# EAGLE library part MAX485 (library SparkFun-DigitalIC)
RS-485 transceiver

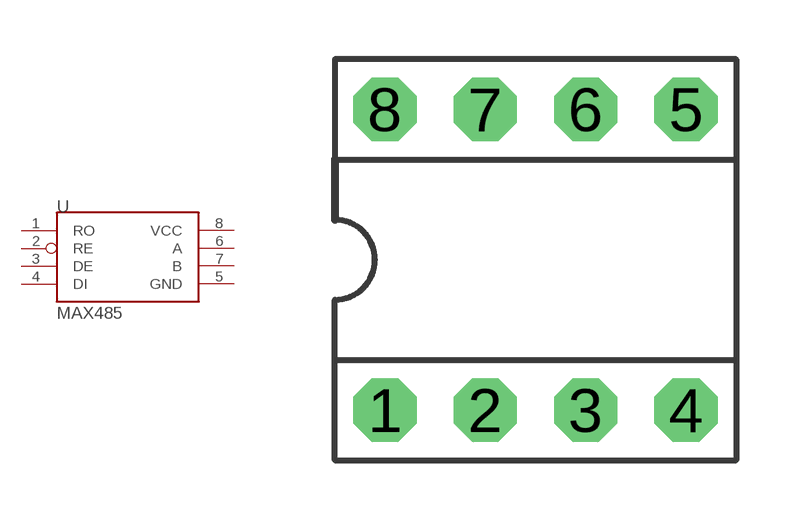
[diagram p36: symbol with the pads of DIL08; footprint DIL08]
Designator prefix -

## MAX485DIL  [DIL08]
1  RO
2  RE
3  DE
4  DI
5  GND
6  A
7  B
8  VCC

## Footprint DIL08 (pad centres in mm)
Dual In Line
drill 0.813 pad 1.6 octagon: 1 -3.81,-3.81; 2 -1.27,-3.81; 3 1.27,-3.81; 4 3.81,-3.81; 5 3.81,3.81; 6 1.27,3.81; 7 -1.27,3.81; 8 -3.81,3.81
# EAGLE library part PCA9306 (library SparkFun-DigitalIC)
Bidirectional I2C level shifter. NOT compatible with all available part number pinout schemes- DOUBLE CHECK!!!

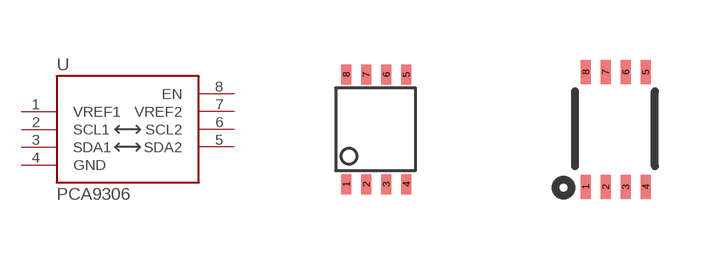
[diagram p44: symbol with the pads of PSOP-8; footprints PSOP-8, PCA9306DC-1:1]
Designator prefix U

## PCA9306 (PROD_ID: IC-10023; VALUE: PCA9306)  [PSOP-8]
1  VREF1
2  SCL1
3  SDA1
4  GND
5  SDA2
6  SCL2
7  VREF2
8  EN

## PCA9306PCA9306DC-1:1 (PROD_ID: IC-10023; VALUE: PCA9306)  [PCA9306DC-1:1]
Pads as for PSOP-8

## Footprint PSOP-8 (pad centres in mm)
smd 0.25 x 0.5: 1 -0.73,-1.37; 2 -0.23,-1.37; 3 0.27,-1.37; 4 0.77,-1.37; 5 0.77,1.38; 6 0.27,1.38; 7 -0.23,1.38; 8 -0.73,1.38

## Footprint PCA9306DC-1:1 (pad centres in mm)
smd 0.25 x 0.602: 1 -0.73,-1.446; 2 -0.23,-1.446; 3 0.27,-1.446; 4 0.77,-1.446; 5 0.77,1.431; 6 0.27,1.431; 7 -0.23,1.431; 8 -0.73,1.431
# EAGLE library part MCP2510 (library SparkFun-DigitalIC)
CAN controller with SPI interface to any MCU. Original design by Microchip.

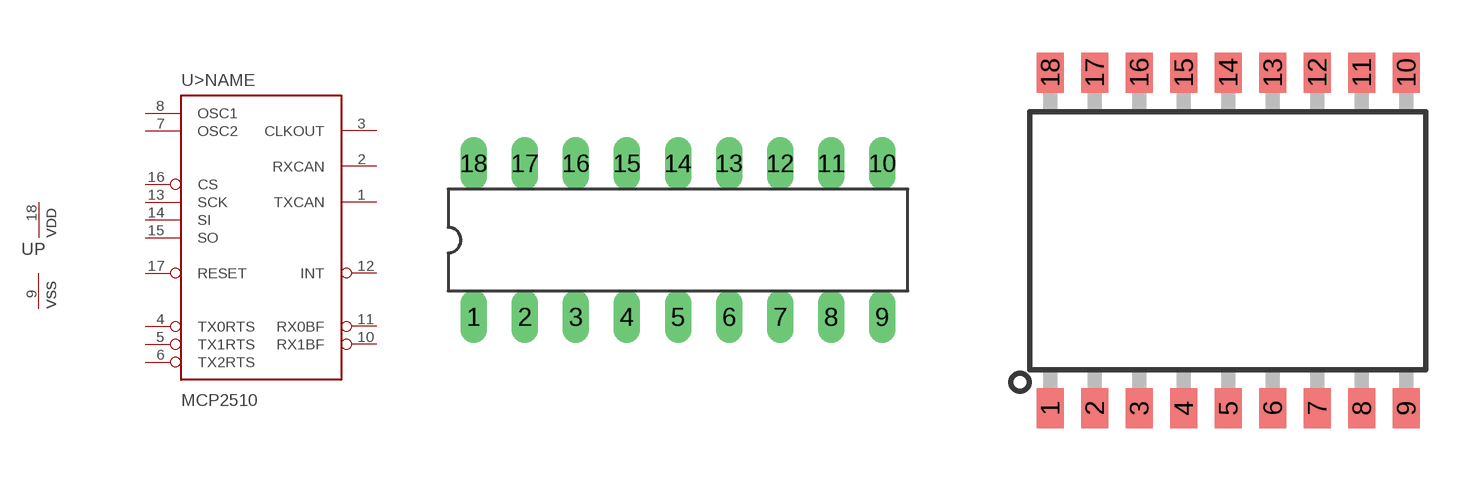
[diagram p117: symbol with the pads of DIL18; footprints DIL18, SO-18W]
Designator prefix U; gates >NAME=MCP2510 P=PWRN-1

## MCP2510P  [DIL18]
1  >NAME:TXCAN  out
2  >NAME:RXCAN  in
3  >NAME:CLKOUT  out
4  >NAME:TX0RTS  in
5  >NAME:TX1RTS  in
6  >NAME:TX2RTS  in
7  >NAME:OSC2  out
8  >NAME:OSC1  in
9  P:VSS  pwr
10  >NAME:RX1BF  out
11  >NAME:RX0BF  out
12  >NAME:INT  out
13  >NAME:SCK  in
14  >NAME:SI  in
15  >NAME:SO  out
16  >NAME:CS  in
17  >NAME:RESET  in
18  P:VDD  pwr

## MCP2510SO (PROD_ID: IC-09906)  [SO-18W]
Pads as for DIL18

## Footprint DIL18 (pad centres in mm)
Dual In Line package type P
drill 0.813 long: 1 -10.16,-3.81; 2 -7.62,-3.81; 3 -5.08,-3.81; 4 -2.54,-3.81; 5 0,-3.81; 6 2.54,-3.81; 7 5.08,-3.81; 8 7.62,-3.81; 9 10.16,-3.81; 10 10.16,3.81; 11 7.62,3.81; 12 5.08,3.81; 13 2.54,3.81; 14 0,3.81; 15 -2.54,3.81; 16 -5.08,3.81; 17 -7.62,3.81; 18 -10.16,3.81

## Footprint SO-18W (pad centres in mm)
Small Outline Wide Plastic Gull Wing 300-mil body, package type SO
smd 0.762 x 1.143: 1 -5.08,-4.788; 2 -3.81,-4.788; 3 -2.54,-4.788; 4 -1.27,-4.788; 5 0,-4.788; 6 1.27,-4.788; 7 2.54,-4.788; 8 3.81,-4.788; 9 5.08,-4.788; 10 5.08,4.788; 11 3.81,4.788; 12 2.54,4.788; 13 1.27,4.788; 14 0,4.788; 15 -1.27,4.788; 16 -2.54,4.788; 17 -3.81,4.788; 18 -5.08,4.788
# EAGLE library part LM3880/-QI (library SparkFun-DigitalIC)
Simple Power Sequencer Precision enable pin & 3 open-drain output flags Input Voltage Range of 2.7 V to 5.5 V Power-Up and Power-Down Control LM3880MF-1XY (Timing Designator) AF16ms AE2ms AA10ms AB30ms AC60ms AD120ms The timing sequence of the LM3880 is controlled entirely by the enable (EN) pin. Upon power up, all the flags are held low until this precision enable is pulled high

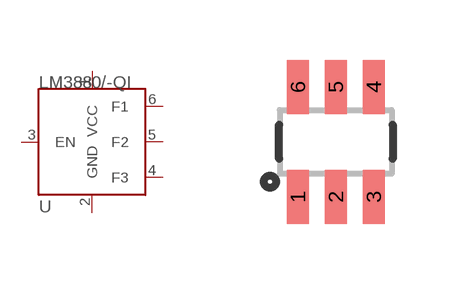
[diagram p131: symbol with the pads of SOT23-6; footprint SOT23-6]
Designator prefix U

## LM3880/-QI (PROD_ID: PROTOTYPE; VALUE: LM3880)  [SOT23-6]
1  VCC
2  GND
3  EN
4  F3
5  F2
6  F1

## Footprint SOT23-6 (pad centres in mm)
smd 0.55 x 1.35: 1 -0.95,-1.375; 2 0,-1.375; 3 0.95,-1.375; 4 0.95,1.375; 5 0,1.375; 6 -0.95,1.375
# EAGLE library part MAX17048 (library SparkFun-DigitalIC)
Micropower 1-Cell Li+ ModelGauge

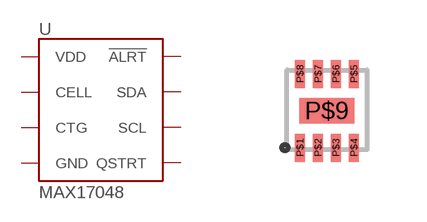
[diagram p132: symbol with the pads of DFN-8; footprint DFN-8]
Designator prefix -

## MAX17048DFN8  [DFN-8]
P$1  CTG  in
P$2  CELL  in
P$3  VDD
P$4  GND
P$5  !ALRT
P$6  QSTRT
P$7  SCL  out
P$8  SDA  in
P$9  GND

## Footprint DFN-8 (pad centres in mm)
smd 0.25 x 0.7: P$1 -0.688,-0.92; P$2 -0.238,-0.92; P$3 0.212,-0.92; P$4 0.662,-0.92; P$5 0.662,0.93; P$6 0.212,0.93; P$7 -0.238,0.93; P$8 -0.688,0.93
smd 1.37 x 0.64: P$9 -0.013,0.005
